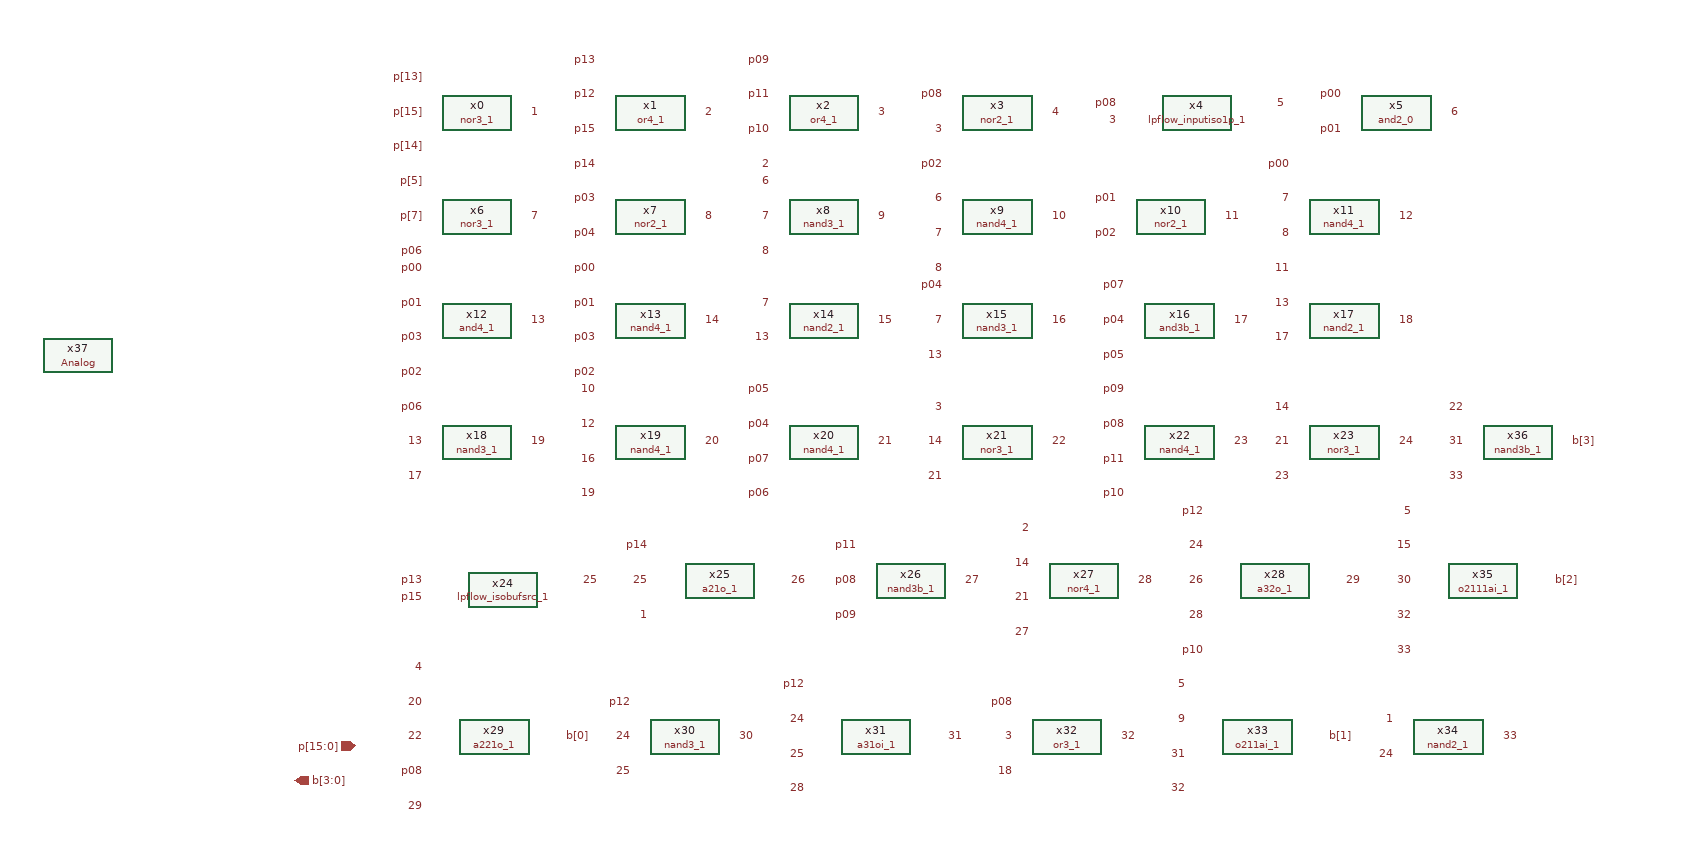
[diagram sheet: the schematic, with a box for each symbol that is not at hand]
v {xschem version=3.4.5 file_version=1.2
}
G {}
K {}
V {}
S {}
E {}
C {devices/ipin.sym} -460 250 0 0 {name=p15 lab=p[15:0]}
C {sky130_stdcells/nor3_1.sym} -320 -480 0 0 {name=x0 VGND=VGND VNB=VNB VPB=VPB VPWR=VPWR prefix=sky130_fd_sc_hd__ }
C {sky130_stdcells/or4_1.sym} -120 -480 0 0 {name=x1 VGND=VGND VNB=VNB VPB=VPB VPWR=VPWR prefix=sky130_fd_sc_hd__ }
C {sky130_stdcells/or4_1.sym} 80 -480 0 0 {name=x2 VGND=VGND VNB=VNB VPB=VPB VPWR=VPWR prefix=sky130_fd_sc_hd__ }
C {sky130_stdcells/nor2_1.sym} 280 -480 0 0 {name=x3 VGND=VGND VNB=VNB VPB=VPB VPWR=VPWR prefix=sky130_fd_sc_hd__ }
C {sky130_stdcells/lpflow_inputiso1p_1.sym} 510 -480 0 0 {name=x4 VGND=VGND VNB=VNB VPB=VPB VPWR=VPWR prefix=sky130_fd_sc_hd__ }
C {sky130_stdcells/and2_0.sym} 740 -480 0 0 {name=x5 VGND=VGND VNB=VNB VPB=VPB VPWR=VPWR prefix=sky130_fd_sc_hd__ }
C {sky130_stdcells/nor3_1.sym} -320 -360 0 0 {name=x6 VGND=VGND VNB=VNB VPB=VPB VPWR=VPWR prefix=sky130_fd_sc_hd__ }
C {sky130_stdcells/nor2_1.sym} -120 -360 0 0 {name=x7 VGND=VGND VNB=VNB VPB=VPB VPWR=VPWR prefix=sky130_fd_sc_hd__ }
C {sky130_stdcells/nand3_1.sym} 80 -360 0 0 {name=x8 VGND=VGND VNB=VNB VPB=VPB VPWR=VPWR prefix=sky130_fd_sc_hd__ }
C {sky130_stdcells/nand4_1.sym} 280 -360 0 0 {name=x9 VGND=VGND VNB=VNB VPB=VPB VPWR=VPWR prefix=sky130_fd_sc_hd__ }
C {sky130_stdcells/nor2_1.sym} 480 -360 0 0 {name=x10 VGND=VGND VNB=VNB VPB=VPB VPWR=VPWR prefix=sky130_fd_sc_hd__ }
C {sky130_stdcells/nand4_1.sym} 680 -360 0 0 {name=x11 VGND=VGND VNB=VNB VPB=VPB VPWR=VPWR prefix=sky130_fd_sc_hd__ }
C {sky130_stdcells/and4_1.sym} -320 -240 0 0 {name=x12 VGND=VGND VNB=VNB VPB=VPB VPWR=VPWR prefix=sky130_fd_sc_hd__ }
C {sky130_stdcells/nand4_1.sym} -120 -240 0 0 {name=x13 VGND=VGND VNB=VNB VPB=VPB VPWR=VPWR prefix=sky130_fd_sc_hd__ }
C {sky130_stdcells/nand2_1.sym} 80 -240 0 0 {name=x14 VGND=VGND VNB=VNB VPB=VPB VPWR=VPWR prefix=sky130_fd_sc_hd__ }
C {sky130_stdcells/nand3_1.sym} 280 -240 0 0 {name=x15 VGND=VGND VNB=VNB VPB=VPB VPWR=VPWR prefix=sky130_fd_sc_hd__ }
C {sky130_stdcells/and3b_1.sym} 490 -240 0 0 {name=x16 VGND=VGND VNB=VNB VPB=VPB VPWR=VPWR prefix=sky130_fd_sc_hd__ }
C {sky130_stdcells/nand2_1.sym} 680 -240 0 0 {name=x17 VGND=VGND VNB=VNB VPB=VPB VPWR=VPWR prefix=sky130_fd_sc_hd__ }
C {sky130_stdcells/nand3_1.sym} -320 -100 0 0 {name=x18 VGND=VGND VNB=VNB VPB=VPB VPWR=VPWR prefix=sky130_fd_sc_hd__ }
C {sky130_stdcells/nand4_1.sym} -120 -100 0 0 {name=x19 VGND=VGND VNB=VNB VPB=VPB VPWR=VPWR prefix=sky130_fd_sc_hd__ }
C {sky130_stdcells/nand4_1.sym} 80 -100 0 0 {name=x20 VGND=VGND VNB=VNB VPB=VPB VPWR=VPWR prefix=sky130_fd_sc_hd__ }
C {sky130_stdcells/nor3_1.sym} 280 -100 0 0 {name=x21 VGND=VGND VNB=VNB VPB=VPB VPWR=VPWR prefix=sky130_fd_sc_hd__ }
C {sky130_stdcells/nand4_1.sym} 490 -100 0 0 {name=x22 VGND=VGND VNB=VNB VPB=VPB VPWR=VPWR prefix=sky130_fd_sc_hd__ }
C {sky130_stdcells/nor3_1.sym} 680 -100 0 0 {name=x23 VGND=VGND VNB=VNB VPB=VPB VPWR=VPWR prefix=sky130_fd_sc_hd__ }
C {sky130_stdcells/lpflow_isobufsrc_1.sym} -290 70 0 0 {name=x24 VGND=VGND VNB=VNB VPB=VPB VPWR=VPWR prefix=sky130_fd_sc_hd__ }
C {sky130_stdcells/a21o_1.sym} -40 60 0 0 {name=x25 VGND=VGND VNB=VNB VPB=VPB VPWR=VPWR prefix=sky130_fd_sc_hd__ }
C {sky130_stdcells/nand3b_1.sym} 180 60 0 0 {name=x26 VGND=VGND VNB=VNB VPB=VPB VPWR=VPWR prefix=sky130_fd_sc_hd__ }
C {sky130_stdcells/nor4_1.sym} 380 60 0 0 {name=x27 VGND=VGND VNB=VNB VPB=VPB VPWR=VPWR prefix=sky130_fd_sc_hd__ }
C {sky130_stdcells/a32o_1.sym} 600 60 0 0 {name=x28 VGND=VGND VNB=VNB VPB=VPB VPWR=VPWR prefix=sky130_fd_sc_hd__ }
C {sky130_stdcells/a221o_1.sym} -300 240 0 0 {name=x29 VGND=VGND VNB=VNB VPB=VPB VPWR=VPWR prefix=sky130_fd_sc_hd__ }
C {sky130_stdcells/nand3_1.sym} -80 240 0 0 {name=x30 VGND=VGND VNB=VNB VPB=VPB VPWR=VPWR prefix=sky130_fd_sc_hd__ }
C {sky130_stdcells/a31oi_1.sym} 140 240 0 0 {name=x31 VGND=VGND VNB=VNB VPB=VPB VPWR=VPWR prefix=sky130_fd_sc_hd__ }
C {sky130_stdcells/or3_1.sym} 360 240 0 0 {name=x32 VGND=VGND VNB=VNB VPB=VPB VPWR=VPWR prefix=sky130_fd_sc_hd__ }
C {sky130_stdcells/o211ai_1.sym} 580 240 0 0 {name=x33 VGND=VGND VNB=VNB VPB=VPB VPWR=VPWR prefix=sky130_fd_sc_hd__ }
C {sky130_stdcells/nand2_1.sym} 800 240 0 0 {name=x34 VGND=VGND VNB=VNB VPB=VPB VPWR=VPWR prefix=sky130_fd_sc_hd__ }
C {sky130_stdcells/o2111ai_1.sym} 840 60 0 0 {name=x35 VGND=VGND VNB=VNB VPB=VPB VPWR=VPWR prefix=sky130_fd_sc_hd__ }
C {sky130_stdcells/nand3b_1.sym} 880 -100 0 0 {name=x36 VGND=VGND VNB=VNB VPB=VPB VPWR=VPWR prefix=sky130_fd_sc_hd__ }
C {devices/lab_pin.sym} -380 -520 0 0 {name=p2 sig_type=std_logic lab=p[13]}
C {devices/lab_pin.sym} -380 -480 0 0 {name=p34 sig_type=std_logic lab=p[15]}
C {devices/lab_pin.sym} -380 -440 0 0 {name=p35 sig_type=std_logic lab=p[14]}
C {devices/lab_pin.sym} -180 -540 0 0 {name=p36 sig_type=std_logic lab=p13}
C {devices/lab_pin.sym} -180 -500 0 0 {name=p37 sig_type=std_logic lab=p12}
C {devices/lab_pin.sym} -180 -460 0 0 {name=p38 sig_type=std_logic lab=p15}
C {devices/lab_pin.sym} -180 -420 0 0 {name=p39 sig_type=std_logic lab=p14}
C {devices/lab_pin.sym} 20 -540 0 0 {name=p40 sig_type=std_logic lab=p09}
C {devices/lab_pin.sym} 20 -500 0 0 {name=p42 sig_type=std_logic lab=p11}
C {devices/lab_pin.sym} 20 -460 0 0 {name=p43 sig_type=std_logic lab=p10}
C {devices/lab_pin.sym} -260 -480 2 0 {name=p44 sig_type=std_logic lab=1}
C {devices/lab_pin.sym} -60 -480 2 0 {name=p45 sig_type=std_logic lab=2}
C {devices/lab_pin.sym} 20 -420 0 0 {name=p46 sig_type=std_logic lab=2}
C {devices/lab_pin.sym} 140 -480 2 0 {name=p47 sig_type=std_logic lab=3}
C {devices/lab_pin.sym} 220 -500 0 0 {name=p49 sig_type=std_logic lab=p08}
C {devices/lab_pin.sym} 220 -460 0 0 {name=p51 sig_type=std_logic lab=3}
C {devices/lab_pin.sym} 340 -480 2 0 {name=p53 sig_type=std_logic lab=4}
C {devices/lab_pin.sym} 420 -490 0 0 {name=p54 sig_type=std_logic lab=p08}
C {devices/lab_pin.sym} 420 -470 0 0 {name=p55 sig_type=std_logic lab=3}
C {devices/lab_pin.sym} 600 -490 2 0 {name=p56 sig_type=std_logic lab=5}
C {devices/lab_pin.sym} 680 -500 0 0 {name=p57 sig_type=std_logic lab=p00}
C {devices/lab_pin.sym} 680 -460 0 0 {name=p58 sig_type=std_logic lab=p01}
C {devices/lab_pin.sym} 800 -480 2 0 {name=p59 sig_type=std_logic lab=6}
C {devices/lab_pin.sym} -380 -400 0 0 {name=p60 sig_type=std_logic lab=p[5]}
C {devices/lab_pin.sym} -380 -360 0 0 {name=p61 sig_type=std_logic lab=p[7]}
C {devices/lab_pin.sym} -380 -320 0 0 {name=p62 sig_type=std_logic lab=p06}
C {devices/lab_pin.sym} -260 -360 2 0 {name=p63 sig_type=std_logic lab=7}
C {devices/lab_pin.sym} -180 -380 0 0 {name=p64 sig_type=std_logic lab=p03}
C {devices/lab_pin.sym} -180 -340 0 0 {name=p65 sig_type=std_logic lab=p04}
C {devices/lab_pin.sym} -60 -360 2 0 {name=p66 sig_type=std_logic lab=8}
C {devices/lab_pin.sym} 20 -400 0 0 {name=p67 sig_type=std_logic lab=6}
C {devices/lab_pin.sym} 20 -360 0 0 {name=p68 sig_type=std_logic lab=7}
C {devices/lab_pin.sym} 20 -320 0 0 {name=p69 sig_type=std_logic lab=8}
C {devices/lab_pin.sym} 140 -360 2 0 {name=p70 sig_type=std_logic lab=9}
C {devices/lab_pin.sym} 220 -420 0 0 {name=p72 sig_type=std_logic lab=p02}
C {devices/lab_pin.sym} 220 -340 0 0 {name=p73 sig_type=std_logic lab=7}
C {devices/lab_pin.sym} 220 -380 0 0 {name=p74 sig_type=std_logic lab=6}
C {devices/lab_pin.sym} 220 -300 0 0 {name=p75 sig_type=std_logic lab=8}
C {devices/lab_pin.sym} 340 -360 2 0 {name=p76 sig_type=std_logic lab=10}
C {devices/lab_pin.sym} 420 -380 0 0 {name=p77 sig_type=std_logic lab=p01}
C {devices/lab_pin.sym} 420 -340 0 0 {name=p78 sig_type=std_logic lab=p02}
C {devices/lab_pin.sym} 540 -360 2 0 {name=p79 sig_type=std_logic lab=11}
C {devices/lab_pin.sym} 620 -420 0 0 {name=p80 sig_type=std_logic lab=p00}
C {devices/lab_pin.sym} 620 -380 0 0 {name=p81 sig_type=std_logic lab=7}
C {devices/lab_pin.sym} 620 -340 0 0 {name=p82 sig_type=std_logic lab=8}
C {devices/lab_pin.sym} 620 -300 0 0 {name=p83 sig_type=std_logic lab=11}
C {devices/lab_pin.sym} 740 -360 2 0 {name=p84 sig_type=std_logic lab=12}
C {devices/lab_pin.sym} -380 -300 0 0 {name=p85 sig_type=std_logic lab=p00}
C {devices/lab_pin.sym} -380 -260 0 0 {name=p86 sig_type=std_logic lab=p01}
C {devices/lab_pin.sym} -380 -220 0 0 {name=p87 sig_type=std_logic lab=p03}
C {devices/lab_pin.sym} -380 -180 0 0 {name=p88 sig_type=std_logic lab=p02}
C {devices/lab_pin.sym} -260 -240 2 0 {name=p89 sig_type=std_logic lab=13}
C {devices/lab_pin.sym} -180 -300 0 0 {name=p90 sig_type=std_logic lab=p00}
C {devices/lab_pin.sym} -180 -260 0 0 {name=p91 sig_type=std_logic lab=p01}
C {devices/lab_pin.sym} -180 -220 0 0 {name=p92 sig_type=std_logic lab=p03}
C {devices/lab_pin.sym} -180 -180 0 0 {name=p93 sig_type=std_logic lab=p02}
C {devices/lab_pin.sym} -60 -240 2 0 {name=p94 sig_type=std_logic lab=14}
C {devices/lab_pin.sym} 20 -260 0 0 {name=p95 sig_type=std_logic lab=7}
C {devices/lab_pin.sym} 20 -220 0 0 {name=p96 sig_type=std_logic lab=13}
C {devices/lab_pin.sym} 140 -240 2 0 {name=p97 sig_type=std_logic lab=15}
C {devices/lab_pin.sym} 220 -280 0 0 {name=p98 sig_type=std_logic lab=p04}
C {devices/lab_pin.sym} 220 -240 0 0 {name=p99 sig_type=std_logic lab=7}
C {devices/lab_pin.sym} 220 -200 0 0 {name=p100 sig_type=std_logic lab=13}
C {devices/lab_pin.sym} 340 -240 2 0 {name=p101 sig_type=std_logic lab=16}
C {devices/lab_pin.sym} 430 -280 0 0 {name=p102 sig_type=std_logic lab=p07}
C {devices/lab_pin.sym} 430 -240 0 0 {name=p103 sig_type=std_logic lab=p04}
C {devices/lab_pin.sym} 430 -200 0 0 {name=p104 sig_type=std_logic lab=p05}
C {devices/lab_pin.sym} 550 -240 2 0 {name=p105 sig_type=std_logic lab=17}
C {devices/lab_pin.sym} 620 -260 0 0 {name=p106 sig_type=std_logic lab=13}
C {devices/lab_pin.sym} 620 -220 0 0 {name=p107 sig_type=std_logic lab=17}
C {devices/lab_pin.sym} 740 -240 2 0 {name=p108 sig_type=std_logic lab=18}
C {devices/lab_pin.sym} -380 -140 0 0 {name=p109 sig_type=std_logic lab=p06}
C {devices/lab_pin.sym} -380 -100 0 0 {name=p110 sig_type=std_logic lab=13}
C {devices/lab_pin.sym} -380 -60 0 0 {name=p111 sig_type=std_logic lab=17}
C {devices/lab_pin.sym} -260 -100 2 0 {name=p112 sig_type=std_logic lab=19}
C {devices/lab_pin.sym} -180 -160 0 0 {name=p113 sig_type=std_logic lab=10}
C {devices/lab_pin.sym} -180 -120 0 0 {name=p114 sig_type=std_logic lab=12}
C {devices/lab_pin.sym} -180 -80 0 0 {name=p115 sig_type=std_logic lab=16}
C {devices/lab_pin.sym} -180 -40 0 0 {name=p116 sig_type=std_logic lab=19}
C {devices/lab_pin.sym} -60 -100 2 0 {name=p117 sig_type=std_logic lab=20}
C {devices/lab_pin.sym} 20 -160 0 0 {name=p118 sig_type=std_logic lab=p05}
C {devices/lab_pin.sym} 20 -120 0 0 {name=p119 sig_type=std_logic lab=p04}
C {devices/lab_pin.sym} 20 -80 0 0 {name=p120 sig_type=std_logic lab=p07}
C {devices/lab_pin.sym} 20 -40 0 0 {name=p121 sig_type=std_logic lab=p06}
C {devices/lab_pin.sym} 140 -100 2 0 {name=p122 sig_type=std_logic lab=21}
C {devices/lab_pin.sym} 220 -140 0 0 {name=p123 sig_type=std_logic lab=3}
C {devices/lab_pin.sym} 220 -100 0 0 {name=p124 sig_type=std_logic lab=14}
C {devices/lab_pin.sym} 220 -60 0 0 {name=p125 sig_type=std_logic lab=21}
C {devices/lab_pin.sym} 340 -100 2 0 {name=p126 sig_type=std_logic lab=22}
C {devices/lab_pin.sym} 430 -160 0 0 {name=p127 sig_type=std_logic lab=p09}
C {devices/lab_pin.sym} 430 -120 0 0 {name=p128 sig_type=std_logic lab=p08}
C {devices/lab_pin.sym} 430 -80 0 0 {name=p129 sig_type=std_logic lab=p11}
C {devices/lab_pin.sym} 430 -40 0 0 {name=p130 sig_type=std_logic lab=p10}
C {devices/lab_pin.sym} 550 -100 2 0 {name=p131 sig_type=std_logic lab=23}
C {devices/lab_pin.sym} 620 -140 0 0 {name=p132 sig_type=std_logic lab=14}
C {devices/lab_pin.sym} 620 -100 0 0 {name=p133 sig_type=std_logic lab=21}
C {devices/lab_pin.sym} 620 -60 0 0 {name=p134 sig_type=std_logic lab=23}
C {devices/lab_pin.sym} 740 -100 2 0 {name=p135 sig_type=std_logic lab=24}
C {devices/lab_pin.sym} -380 60 0 0 {name=p136 sig_type=std_logic lab=p13}
C {devices/lab_pin.sym} -380 80 0 0 {name=p137 sig_type=std_logic lab=p15}
C {devices/lab_pin.sym} -200 60 2 0 {name=p138 sig_type=std_logic lab=25}
C {devices/lab_pin.sym} -120 20 0 0 {name=p139 sig_type=std_logic lab=p14}
C {devices/lab_pin.sym} -120 60 0 0 {name=p140 sig_type=std_logic lab=25}
C {devices/lab_pin.sym} -120 100 0 0 {name=p141 sig_type=std_logic lab=1}
C {devices/lab_pin.sym} 40 60 2 0 {name=p142 sig_type=std_logic lab=26}
C {devices/lab_pin.sym} 120 20 0 0 {name=p143 sig_type=std_logic lab=p11}
C {devices/lab_pin.sym} 120 60 0 0 {name=p144 sig_type=std_logic lab=p08}
C {devices/lab_pin.sym} 120 100 0 0 {name=p145 sig_type=std_logic lab=p09}
C {devices/lab_pin.sym} 240 60 2 0 {name=p146 sig_type=std_logic lab=27}
C {devices/lab_pin.sym} 320 0 0 0 {name=p147 sig_type=std_logic lab=2}
C {devices/lab_pin.sym} 320 40 0 0 {name=p148 sig_type=std_logic lab=14}
C {devices/lab_pin.sym} 320 80 0 0 {name=p149 sig_type=std_logic lab=21}
C {devices/lab_pin.sym} 320 120 0 0 {name=p150 sig_type=std_logic lab=27}
C {devices/lab_pin.sym} 440 60 2 0 {name=p151 sig_type=std_logic lab=28}
C {devices/lab_pin.sym} 520 -20 0 0 {name=p152 sig_type=std_logic lab=p12}
C {devices/lab_pin.sym} 520 20 0 0 {name=p153 sig_type=std_logic lab=24}
C {devices/lab_pin.sym} 520 60 0 0 {name=p154 sig_type=std_logic lab=26}
C {devices/lab_pin.sym} 520 100 0 0 {name=p155 sig_type=std_logic lab=28}
C {devices/lab_pin.sym} 520 140 0 0 {name=p156 sig_type=std_logic lab=p10}
C {devices/lab_pin.sym} 680 60 2 0 {name=p157 sig_type=std_logic lab=29}
C {devices/lab_pin.sym} -380 160 0 0 {name=p158 sig_type=std_logic lab=4}
C {devices/lab_pin.sym} -380 200 0 0 {name=p159 sig_type=std_logic lab=20}
C {devices/lab_pin.sym} -380 240 0 0 {name=p160 sig_type=std_logic lab=22}
C {devices/lab_pin.sym} -380 280 0 0 {name=p161 sig_type=std_logic lab=p08}
C {devices/lab_pin.sym} -380 320 0 0 {name=p162 sig_type=std_logic lab=29}
C {devices/lab_pin.sym} -220 240 2 0 {name=p164 sig_type=std_logic lab=b[0]}
C {devices/lab_pin.sym} -140 200 0 0 {name=p165 sig_type=std_logic lab=p12}
C {devices/lab_pin.sym} -140 240 0 0 {name=p166 sig_type=std_logic lab=24}
C {devices/lab_pin.sym} -140 280 0 0 {name=p167 sig_type=std_logic lab=25}
C {devices/lab_pin.sym} -20 240 2 0 {name=p168 sig_type=std_logic lab=30}
C {devices/lab_pin.sym} 60 180 0 0 {name=p169 sig_type=std_logic lab=p12}
C {devices/lab_pin.sym} 60 220 0 0 {name=p170 sig_type=std_logic lab=24}
C {devices/lab_pin.sym} 60 260 0 0 {name=p171 sig_type=std_logic lab=25}
C {devices/lab_pin.sym} 60 300 0 0 {name=p172 sig_type=std_logic lab=28}
C {devices/lab_pin.sym} 220 240 2 0 {name=p173 sig_type=std_logic lab=31}
C {devices/lab_pin.sym} 300 200 0 0 {name=p174 sig_type=std_logic lab=p08}
C {devices/lab_pin.sym} 300 240 0 0 {name=p175 sig_type=std_logic lab=3}
C {devices/lab_pin.sym} 300 280 0 0 {name=p176 sig_type=std_logic lab=18}
C {devices/lab_pin.sym} 420 240 2 0 {name=p177 sig_type=std_logic lab=32}
C {devices/lab_pin.sym} 500 180 0 0 {name=p178 sig_type=std_logic lab=5}
C {devices/lab_pin.sym} 500 220 0 0 {name=p179 sig_type=std_logic lab=9}
C {devices/lab_pin.sym} 500 260 0 0 {name=p180 sig_type=std_logic lab=31}
C {devices/lab_pin.sym} 500 300 0 0 {name=p181 sig_type=std_logic lab=32}
C {devices/lab_pin.sym} 740 220 0 0 {name=p184 sig_type=std_logic lab=1}
C {devices/lab_pin.sym} 740 260 0 0 {name=p185 sig_type=std_logic lab=24}
C {devices/lab_pin.sym} 860 240 2 0 {name=p186 sig_type=std_logic lab=33}
C {devices/lab_pin.sym} 760 -20 0 0 {name=p187 sig_type=std_logic lab=5}
C {devices/lab_pin.sym} 760 20 0 0 {name=p188 sig_type=std_logic lab=15}
C {devices/lab_pin.sym} 760 60 0 0 {name=p189 sig_type=std_logic lab=30}
C {devices/lab_pin.sym} 760 100 0 0 {name=p190 sig_type=std_logic lab=32}
C {devices/lab_pin.sym} 760 140 0 0 {name=p191 sig_type=std_logic lab=33}
C {devices/lab_pin.sym} 920 60 2 0 {name=p192 sig_type=std_logic lab=b[2]}
C {devices/lab_pin.sym} 820 -140 0 0 {name=p194 sig_type=std_logic lab=22}
C {devices/lab_pin.sym} 820 -100 0 0 {name=p195 sig_type=std_logic lab=31}
C {devices/lab_pin.sym} 820 -60 0 0 {name=p196 sig_type=std_logic lab=33}
C {Symbol/Analog.sym} -780 -200 0 0 {name=x37}
C {devices/opin.sym} -530 290 0 0 {name=p199 lab=b[3:0] }
C {devices/lab_pin.sym} 940 -100 0 1 {name=p200 lab=b[3] }
C {devices/lab_pin.sym} 660 240 2 0 {name=p50 sig_type=std_logic lab=b[1]}
